One B-rep face of a CAD part: STEP entity #381.
In plain terms, the planar face has unit normal (1, 0, 0).
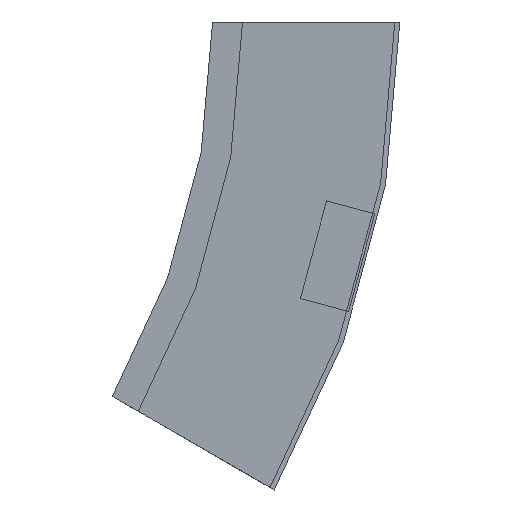
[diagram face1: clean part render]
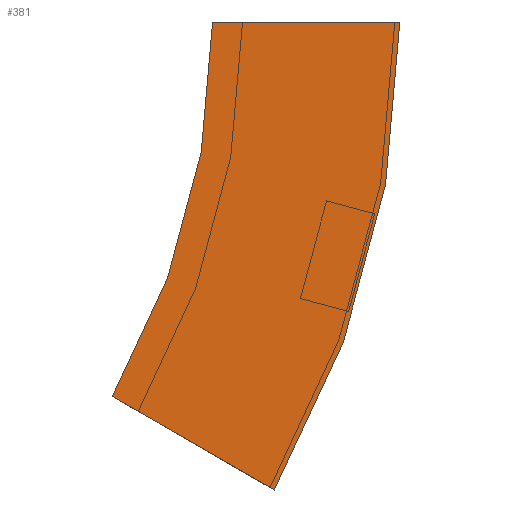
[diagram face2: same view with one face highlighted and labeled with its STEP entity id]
Its self-contained STEP definition (entity closure, numbers rounded to 3 decimals):
#5 = VERTEX_POINT ( 'NONE', #302 ) ;
#21 = CIRCLE ( 'NONE', #232, 375. ) ;
#33 = AXIS2_PLACEMENT_3D ( 'NONE', #175, #87, #308 ) ;
#34 = DIRECTION ( 'NONE',  ( 1., 0., 0. ) ) ;
#81 = VERTEX_POINT ( 'NONE', #192 ) ;
#87 = DIRECTION ( 'NONE',  ( -1., 0., 0. ) ) ;
#98 = CARTESIAN_POINT ( 'NONE',  ( 0., 300., 0. ) ) ;
#99 = VECTOR ( 'NONE', #342, 1000. ) ;
#125 = CIRCLE ( 'NONE', #230, 300. ) ;
#174 = VERTEX_POINT ( 'NONE', #332 ) ;
#175 = CARTESIAN_POINT ( 'NONE',  ( 0., -75., 0. ) ) ;
#192 = CARTESIAN_POINT ( 'NONE',  ( 0., -75., 0. ) ) ;
#200 = LINE ( 'NONE', #334, #99 ) ;
#211 = EDGE_CURVE ( 'NONE', #5, #457, #556, .T. ) ;
#230 = AXIS2_PLACEMENT_3D ( 'NONE', #98, #455, #326 ) ;
#232 = AXIS2_PLACEMENT_3D ( 'NONE', #555, #34, #478 ) ;
#241 = VECTOR ( 'NONE', #277, 1000. ) ;
#277 = DIRECTION ( 'NONE',  ( 0., 0.866, 0.5 ) ) ;
#287 = ORIENTED_EDGE ( 'NONE', *, *, #423, .F. ) ;
#294 = ORIENTED_EDGE ( 'NONE', *, *, #542, .F. ) ;
#302 = CARTESIAN_POINT ( 'NONE',  ( 0., -24.76, -187.5 ) ) ;
#308 = DIRECTION ( 'NONE',  ( 0., 0., 1. ) ) ;
#326 = DIRECTION ( 'NONE',  ( 0., -1., 0. ) ) ;
#332 = CARTESIAN_POINT ( 'NONE',  ( 0., 0., 0. ) ) ;
#334 = CARTESIAN_POINT ( 'NONE',  ( 0., -75., 0. ) ) ;
#342 = DIRECTION ( 'NONE',  ( 0., 1., 0. ) ) ;
#381 = ADVANCED_FACE ( 'NONE', ( #402 ), #529, .F. ) ;
#402 = FACE_OUTER_BOUND ( 'NONE', #432, .T. ) ;
#422 = ORIENTED_EDGE ( 'NONE', *, *, #211, .T. ) ;
#423 = EDGE_CURVE ( 'NONE', #174, #457, #125, .T. ) ;
#432 = EDGE_LOOP ( 'NONE', ( #287, #294, #546, #422 ) ) ;
#455 = DIRECTION ( 'NONE',  ( 1., 0., 0. ) ) ;
#457 = VERTEX_POINT ( 'NONE', #459 ) ;
#459 = CARTESIAN_POINT ( 'NONE',  ( 0., 40.192, -150. ) ) ;
#478 = DIRECTION ( 'NONE',  ( 0., -1., 0. ) ) ;
#518 = CARTESIAN_POINT ( 'NONE',  ( 0., -24.76, -187.5 ) ) ;
#529 = PLANE ( 'NONE',  #33 ) ;
#542 = EDGE_CURVE ( 'NONE', #81, #174, #200, .T. ) ;
#546 = ORIENTED_EDGE ( 'NONE', *, *, #563, .T. ) ;
#555 = CARTESIAN_POINT ( 'NONE',  ( 0., 300., 0. ) ) ;
#556 = LINE ( 'NONE', #518, #241 ) ;
#563 = EDGE_CURVE ( 'NONE', #81, #5, #21, .T. ) ;
